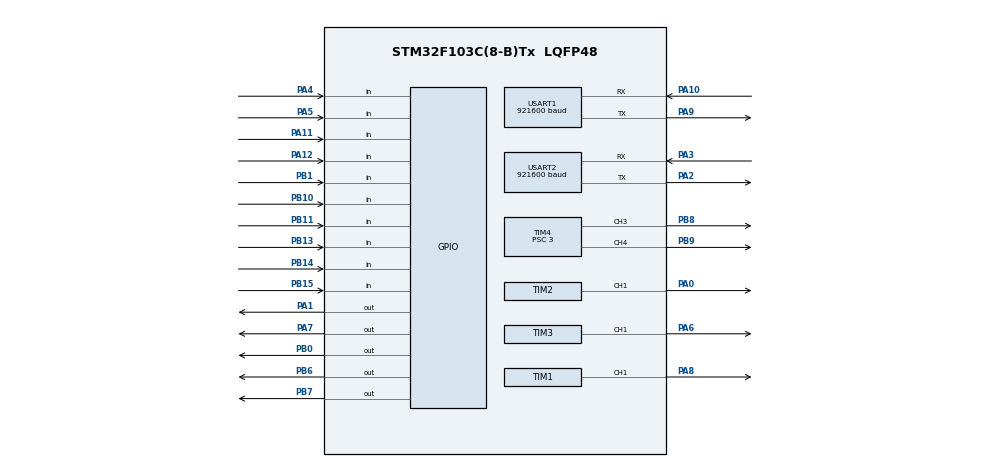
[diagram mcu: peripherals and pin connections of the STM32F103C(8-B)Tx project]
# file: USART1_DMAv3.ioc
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Dma.Request0=USART1_RX
Dma.Request1=USART2_RX
Dma.USART1_RX.0.Direction=DMA_PERIPH_TO_MEMORY
Dma.USART1_RX.0.Instance=DMA1_Channel5
Dma.USART1_RX.0.MemDataAlignment=DMA_MDATAALIGN_BYTE
Dma.USART1_RX.0.MemInc=DMA_MINC_ENABLE
Dma.USART1_RX.0.Mode=DMA_CIRCULAR
Dma.USART1_RX.0.PeriphDataAlignment=DMA_PDATAALIGN_BYTE
Dma.USART1_RX.0.PeriphInc=DMA_PINC_DISABLE
Dma.USART1_RX.0.Priority=DMA_PRIORITY_LOW
Dma.USART2_RX.1.Direction=DMA_PERIPH_TO_MEMORY
Dma.USART2_RX.1.Instance=DMA1_Channel6
Dma.USART2_RX.1.MemDataAlignment=DMA_MDATAALIGN_BYTE
Dma.USART2_RX.1.MemInc=DMA_MINC_ENABLE
Dma.USART2_RX.1.Mode=DMA_NORMAL
Dma.USART2_RX.1.PeriphDataAlignment=DMA_PDATAALIGN_BYTE
Dma.USART2_RX.1.PeriphInc=DMA_PINC_DISABLE
Dma.USART2_RX.1.Priority=DMA_PRIORITY_LOW
Mcu.Family=STM32F1
Mcu.Name=STM32F103C(8-B)Tx
Mcu.Package=LQFP48
NVIC.DMA1_Channel5_IRQn=true\:0\:0\:false\:false\:true\:false\:true\:true
NVIC.DMA1_Channel6_IRQn=true\:0\:0\:false\:false\:true\:false\:true\:true
NVIC.PriorityGroup=NVIC_PRIORITYGROUP_4
NVIC.USART2_IRQn=true\:0\:0\:false\:false\:true\:true\:true\:true
PA0-WKUP.Signal=S_TIM2_CH1_ETR
PA1.Signal=GPIO_Output
PA10.Mode=Asynchronous
PA10.Signal=USART1_RX
PA11.Signal=GPIO_Input
PA12.Signal=GPIO_Input
PA13.Mode=Serial_Wire
PA13.Signal=SYS_JTMS-SWDIO
PA14.Mode=Serial_Wire
PA14.Signal=SYS_JTCK-SWCLK
PA2.Mode=Asynchronous
PA2.Signal=USART2_TX
PA3.Mode=Asynchronous
PA3.Signal=USART2_RX
PA4.Signal=GPIO_Input
PA5.Signal=GPIO_Input
PA6.Signal=S_TIM3_CH1
PA7.Signal=GPIO_Output
PA8.Signal=S_TIM1_CH1
PA9.Mode=Asynchronous
PA9.Signal=USART1_TX
PB0.Signal=GPIO_Output
PB1.Signal=GPIO_Input
PB10.Signal=GPIO_Input
PB11.Signal=GPIO_Input
PB13.Signal=GPIO_Input
PB14.Signal=GPIO_Input
PB15.Signal=GPIO_Input
PB6.Signal=GPIO_Output
PB7.Signal=GPIO_Output
PB8.Signal=S_TIM4_CH3
PB9.Signal=S_TIM4_CH4
PD0-OSC_IN.Mode=HSE-External-Oscillator
PD0-OSC_IN.Signal=RCC_OSC_IN
PD1-OSC_OUT.Mode=HSE-External-Oscillator
PD1-OSC_OUT.Signal=RCC_OSC_OUT
ProjectManager.HeapSize=0x200
ProjectManager.StackSize=0x400
ProjectManager.TargetToolchain=Makefile
RCC.AHBFreq_Value=16000000
RCC.APB1Freq_Value=16000000
RCC.APB1TimFreq_Value=16000000
RCC.APB2Freq_Value=16000000
RCC.APB2TimFreq_Value=16000000
RCC.HCLKFreq_Value=16000000
RCC.PLLMUL=RCC_PLL_MUL4
RCC.SYSCLKFreq_VALUE=16000000
RCC.SYSCLKSource=RCC_SYSCLKSOURCE_PLLCLK
RCC.USBFreq_Value=16000000
SH.S_TIM1_CH1.0=TIM1_CH1,PWM Generation1 CH1
SH.S_TIM2_CH1_ETR.0=TIM2_CH1,PWM Generation1 CH1
SH.S_TIM3_CH1.0=TIM3_CH1,PWM Generation1 CH1
SH.S_TIM4_CH3.0=TIM4_CH3,PWM Generation3 CH3
SH.S_TIM4_CH4.0=TIM4_CH4,PWM Generation4 CH4
TIM1.AutoReloadPreload=TIM_AUTORELOAD_PRELOAD_ENABLE
TIM1.Channel-PWM\ Generation1\ CH1=TIM_CHANNEL_1
TIM1.OCPolarity_1=TIM_OCPOLARITY_HIGH
TIM1.Period=1023
TIM1.Pulse-PWM\ Generation1\ CH1=512
TIM2.Channel-PWM\ Generation1\ CH1=TIM_CHANNEL_1
TIM3.Channel-PWM\ Generation1\ CH1=TIM_CHANNEL_1
TIM4.Channel-PWM\ Generation3\ CH3=TIM_CHANNEL_3
TIM4.Channel-PWM\ Generation4\ CH4=TIM_CHANNEL_4
TIM4.Period=1023
TIM4.Prescaler=3
TIM4.Pulse-PWM\ Generation3\ CH3=256
TIM4.Pulse-PWM\ Generation4\ CH4=128 
USART1.BaudRate=921600
USART1.VirtualMode=VM_ASYNC
USART2.BaudRate=921600
USART2.VirtualMode=VM_ASYNC
VP_TIM1_VS_ClockSourceINT.Mode=Internal
board=custom

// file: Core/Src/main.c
/* USER CODE BEGIN Header */
/**
  ******************************************************************************
  * @file           : main.c
  * @brief          : Main program body
  ******************************************************************************
  * @attention
  *
  * Copyright (c) 2025 STMicroelectronics.
  * All rights reserved.
  *
  * This software is licensed under terms that can be found in the LICENSE file
  * in the root directory of this software component.
  * If no LICENSE file comes with this software, it is provided AS-IS.
  *
  ******************************************************************************
  */
/* USER CODE END Header */
#include "main.h"
#include "dma.h"
#include "tim.h"
#include "usart.h"
#include "gpio.h"

void SystemClock_Config(void);

/* USER CODE BEGIN 0 */
void setup();
void loop();
/* USER CODE END 0 */

int main(void)
{

  /* MCU Configuration--------------------------------------------------------*/

  /* Reset of all peripherals, Initializes the Flash interface and the Systick. */
  HAL_Init();

  /* Configure the system clock */
  SystemClock_Config();

  /* Initialize all configured peripherals */
  MX_GPIO_Init();
  MX_DMA_Init();
  MX_USART2_UART_Init();
  MX_USART1_UART_Init();
  MX_TIM1_Init();
  MX_TIM2_Init();
  MX_TIM3_Init();
  MX_TIM4_Init();
  /* USER CODE BEGIN 2 */
  setup();
  /* USER CODE END 2 */

  /* Infinite loop */
  while (1)
  {

    /* USER CODE BEGIN 3 */
      loop();
  }
  /* USER CODE END 3 */
}

void SystemClock_Config(void)
{
  RCC_OscInitTypeDef RCC_OscInitStruct = {0};
  RCC_ClkInitTypeDef RCC_ClkInitStruct = {0};

  /** Initializes the RCC Oscillators according to the specified parameters
  * in the RCC_OscInitTypeDef structure.
  */
  RCC_OscInitStruct.OscillatorType = RCC_OSCILLATORTYPE_HSI;
  RCC_OscInitStruct.HSIState = RCC_HSI_ON;
  RCC_OscInitStruct.HSICalibrationValue = RCC_HSICALIBRATION_DEFAULT;
  RCC_OscInitStruct.PLL.PLLState = RCC_PLL_ON;
  RCC_OscInitStruct.PLL.PLLSource = RCC_PLLSOURCE_HSI_DIV2;
  RCC_OscInitStruct.PLL.PLLMUL = RCC_PLL_MUL15;
  if (HAL_RCC_OscConfig(&RCC_OscInitStruct) != HAL_OK)
  {
    Error_Handler();
  }

  /** Initializes the CPU, AHB and APB buses clocks
  */
  RCC_ClkInitStruct.ClockType = RCC_CLOCKTYPE_HCLK|RCC_CLOCKTYPE_SYSCLK
                              |RCC_CLOCKTYPE_PCLK1|RCC_CLOCKTYPE_PCLK2;
  RCC_ClkInitStruct.SYSCLKSource = RCC_SYSCLKSOURCE_PLLCLK;
  RCC_ClkInitStruct.AHBCLKDivider = RCC_SYSCLK_DIV1;
  RCC_ClkInitStruct.APB1CLKDivider = RCC_HCLK_DIV2;
  RCC_ClkInitStruct.APB2CLKDivider = RCC_HCLK_DIV1;

  if (HAL_RCC_ClockConfig(&RCC_ClkInitStruct, FLASH_LATENCY_2) != HAL_OK)
  {
    Error_Handler();
  }
}

void Error_Handler(void)
{
  __disable_irq();
  while (1)
  {
  }
}
